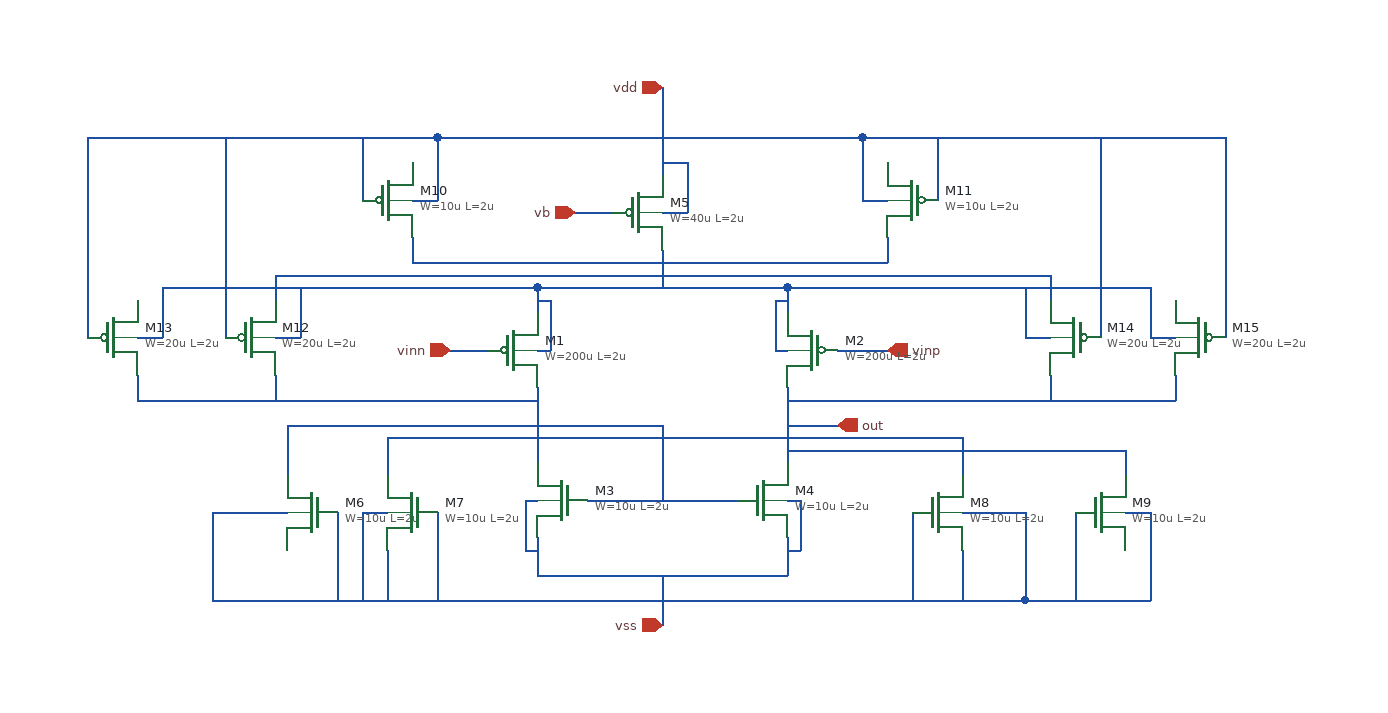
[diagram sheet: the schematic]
v {xschem version=3.4.5 file_version=1.2
}
G {}
K {}
V {}
S {}
E {}
N 420 -210 420 -150 {
lab=out}
N 220 -210 220 -150 {
lab=#net1}
N 260 -120 380 -120 {
lab=#net1}
N 220 -90 220 -60 {
lab=vdd}
N 220 -60 420 -60 {
lab=vdd}
N 420 -90 420 -60 {
lab=vdd}
N 220 -180 320 -180 {
lab=#net1}
N 320 -180 320 -120 {
lab=#net1}
N 220 -290 420 -290 {
lab=#net2}
N 420 -290 420 -270 {
lab=#net2}
N 320 -320 320 -290 {
lab=#net2}
N 320 -60 320 -30 {
lab=vdd}
N 320 -400 320 -380 {
lab=vdd}
N 250 -350 280 -350 {
lab=vb}
N 420 -180 460 -180 {
lab=out}
N 220 -290 220 -270 {
lab=#net2}
N 320 -350 340 -350 {
lab=vdd}
N 340 -390 340 -350 {
lab=vdd}
N 320 -390 340 -390 {
lab=vdd}
N 210 -120 220 -120 {
lab=vdd}
N 210 -120 210 -80 {
lab=vdd}
N 210 -80 220 -80 {
lab=vdd}
N 420 -120 430 -120 {
lab=vdd}
N 430 -120 430 -80 {
lab=vdd}
N 420 -80 430 -80 {
lab=vdd}
N 220 -240 230 -240 {
lab=#net2}
N 230 -280 230 -240 {
lab=#net2}
N 220 -280 230 -280 {
lab=#net2}
N 410 -240 420 -240 {
lab=#net2}
N 410 -280 410 -240 {
lab=#net2}
N 410 -280 420 -280 {
lab=#net2}
N 150 -240 180 -240 {
lab=vinn}
N 460 -240 500 -240 {
lab=vinp}
N 320 -30 320 -20 {
lab=vdd}
N 320 -450 320 -400 {
lab=vdd}
N 20 -180 20 -140 {
lab=#net1}
N 20 -180 220 -180 {
lab=#net1}
N -40 -110 20 -110 {
lab=vdd}
N -40 -110 -40 -40 {
lab=vdd}
N -40 -40 320 -40 {
lab=vdd}
N 560 -110 610 -110 {
lab=vdd}
N 610 -110 610 -40 {
lab=vdd}
N 320 -40 610 -40 {
lab=vdd}
N 80 -110 100 -110 {
lab=vdd}
N 80 -110 80 -40 {
lab=vdd}
N 690 -160 690 -140 {
lab=out}
N 690 -110 710 -110 {
lab=vdd}
N 710 -110 710 -40 {
lab=vdd}
N 610 -40 710 -40 {
lab=vdd}
N 100 -80 100 -40 {
lab=vdd}
N 560 -80 560 -40 {
lab=vdd}
N 100 -160 100 -140 {
lab=#net3}
N 100 -170 560 -170 {
lab=#net3}
N 100 -170 100 -160 {
lab=#net3}
N 420 -160 690 -160 {
lab=out}
N 560 -170 560 -140 {
lab=#net3}
N 120 -330 120 -310 {
lab=#net2}
N 120 -310 320 -310 {
lab=#net2}
N 320 -310 500 -310 {
lab=#net2}
N 500 -330 500 -310 {
lab=#net2}
N 120 -360 140 -360 {
lab=vdd}
N 140 -410 140 -360 {
lab=vdd}
N 140 -410 320 -410 {
lab=vdd}
N 320 -410 480 -410 {
lab=vdd}
N 480 -410 480 -360 {
lab=vdd}
N 480 -360 500 -360 {
lab=vdd}
N -100 -220 -100 -200 {
lab=#net1}
N -100 -200 220 -200 {
lab=#net1}
N 420 -200 730 -200 {
lab=out}
N 730 -220 730 -200 {
lab=out}
N 630 -220 630 -200 {
lab=out}
N 10 -220 10 -200 {
lab=#net1}
N -80 -290 220 -290 {
lab=#net2}
N -80 -290 -80 -250 {
lab=#net2}
N -100 -250 -80 -250 {
lab=#net2}
N 10 -250 30 -250 {
lab=#net2}
N 30 -290 30 -250 {
lab=#net2}
N 420 -290 710 -290 {
lab=#net2}
N 710 -290 710 -250 {
lab=#net2}
N 710 -250 730 -250 {
lab=#net2}
N 610 -250 630 -250 {
lab=#net2}
N 610 -290 610 -250 {
lab=#net2}
N 10 -300 10 -280 {
lab=#net4}
N 10 -300 630 -300 {
lab=#net4}
N 630 -300 630 -280 {
lab=#net4}
N 480 -410 650 -410 {
lab=vdd}
N 60 -410 140 -410 {
lab=vdd}
N 80 -410 80 -360 {
lab=vdd}
N 540 -410 540 -360 {
lab=vdd}
N -140 -410 60 -410 {
lab=vdd}
N -140 -410 -140 -250 {
lab=vdd}
N 650 -410 770 -410 {
lab=vdd}
N 770 -410 770 -250 {
lab=vdd}
N -30 -410 -30 -250 {
lab=vdd}
N 670 -410 670 -250 {
lab=vdd}
N 650 -110 650 -40 {
lab=vdd}
N 520 -110 520 -40 {
lab=vdd}
N 140 -110 140 -40 {
lab=vdd}
N 60 -110 60 -40 {
lab=vdd}
C {devices/ipin.sym} 150 -240 0 0 {name=p9 lab=vinn}
C {devices/ipin.sym} 500 -240 0 1 {name=p5 lab=vinp}
C {devices/ipin.sym} 250 -350 0 0 {name=p2 lab=vb}
C {devices/opin.sym} 460 -180 0 0 {name=p3 lab=out}
C {devices/iopin.sym} 320 -450 0 0 {name=p1 lab=vdd
}
C {devices/iopin.sym} 320 -20 0 0 {name=p4 lab=vss
}
C {primitives/pfet.sym} 300 -350 0 0 {name=M5 
model=pmos
W=40u
L=2u
m=1
}
C {primitives/pfet.sym} 200 -240 0 0 {name=M1 
model=pmos
W=200u
L=2u
m=1
}
C {primitives/pfet.sym} 440 -240 0 1 {name=M2 
model=pmos
W=200u
L=2u
m=1
}
C {primitives/nfet.sym} 240 -120 0 1 {name=M3 
model=nmos
W=10u
L=2u
m=1
}
C {primitives/nfet.sym} 400 -120 0 0 {name=M4 
model=nmos
W=10u
L=2u
m=1
}
C {primitives/nfet.sym} 540 -110 0 0 {name=M8 
model=nmos
W=10u
L=2u
m=1
}
C {primitives/nfet.sym} 40 -110 0 1 {name=M6 
model=nmos
W=10u
L=2u
m=1
}
C {primitives/nfet.sym} 120 -110 0 1 {name=M7 
model=nmos
W=10u
L=2u
m=1
}
C {primitives/nfet.sym} 670 -110 0 0 {name=M9 
model=nmos
W=10u
L=2u
m=1
}
C {primitives/pfet.sym} 100 -360 0 0 {name=M10 
model=pmos
W=10u
L=2u
m=1
}
C {primitives/pfet.sym} 520 -360 0 1 {name=M11 
model=pmos
W=10u
L=2u
m=1
}
C {primitives/pfet.sym} -10 -250 0 0 {name=M12 
model=pmos
W=20u
L=2u
m=1
}
C {primitives/pfet.sym} -120 -250 0 0 {name=M13 
model=pmos
W=20u
L=2u
m=1
}
C {primitives/pfet.sym} 650 -250 0 1 {name=M14 
model=pmos
W=20u
L=2u
m=1
}
C {primitives/pfet.sym} 750 -250 0 1 {name=M15 
model=pmos
W=20u
L=2u
m=1
}
